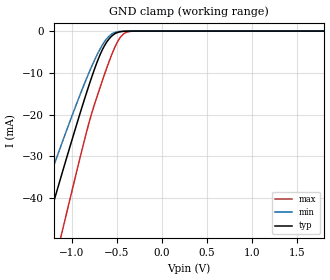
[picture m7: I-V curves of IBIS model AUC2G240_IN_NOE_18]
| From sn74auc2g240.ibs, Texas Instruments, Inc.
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[Model]   AUC2G240_IN_NOE_18
Model_type  Input
Vinl=0.5775
Vinh=1.2675
| variable   typ   min   max
C_comp   2.60pF   2.12pF   3.01pF
[Temperature Range]   40   100   -40
| Ambient temperature   25   85   -40
[Voltage range]   1.8   1.65   1.95
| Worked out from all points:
|   GND clamp passes 1 mA (typ) near -0.55 V on its own axis
[GND Clamp]
| AUC2G240_IN_NOE_18
|   Voltage   I(typ)   I(min)   I(max)
-3.6V     -223.1mA   -186.8mA   -268.3mA
-1.475V   -61.35mA   -49.06mA   -80.92mA
-1.43V    -57.96mA   -46.27mA   -76.89mA
-1.295V   -47.84mA   -37.96mA   -64.81mA
-1.145V   -36.73mA   -28.9mA    -51.37mA
-1.095V   -33.06mA   -25.94mA   -46.89mA
-830mV    -14.34mA   -11.03mA   -23.64mA
-685mV    -5.613mA   -4.259mA   -13.41mA
-560mV    -1.272mA   -762.6uA   -5.827mA
-485mV    -290.6uA   -142.1uA   -2.305mA
-420mV    -55.81uA   -27.03uA   -608.5uA
1.8V      213.9pA    308.4pA    246.3pA
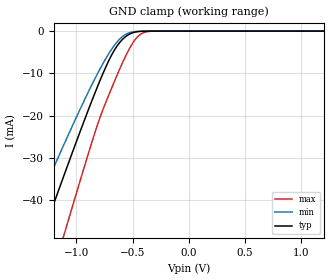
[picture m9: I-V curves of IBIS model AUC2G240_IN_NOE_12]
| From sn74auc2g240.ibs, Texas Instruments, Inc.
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[Model]   AUC2G240_IN_NOE_12
Model_type  Input
Vinl=0.385
Vinh=0.845
| variable   typ   min   max
C_comp   2.62pF   2.21pF   3.02pF
[Temperature Range]   40   100   -40
| Ambient temperature   25   85   -40
[Voltage range]   1.2   1.1   1.3
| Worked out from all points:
|   GND clamp passes 1 mA (typ) near -0.55 V on its own axis
[GND Clamp]
| AUC2G240_IN_NOE_12
|   Voltage   I(typ)   I(min)   I(max)
-3.6V     -223.1mA   -186.8mA   -268.3mA
-1.46V    -60.22mA   -48.13mA   -79.57mA
-1.415V   -56.83mA   -45.34mA   -75.55mA
-1.285V   -47.1mA    -37.35mA   -63.92mA
-1.12V    -34.89mA   -27.41mA   -49.13mA
-1.085V   -32.33mA   -25.35mA   -46mA
-830mV    -14.34mA   -11.03mA   -23.64mA
-690mV    -5.864mA   -4.456mA   -13.74mA
-570mV    -1.488mA   -922uA     -6.381mA
-440mV    -95.43uA   -45.59uA   -977.4uA
-320mV    -2.85uA    -1.757uA   -25.53uA
1.2V      140.4pA    230.7pA    130.8pA
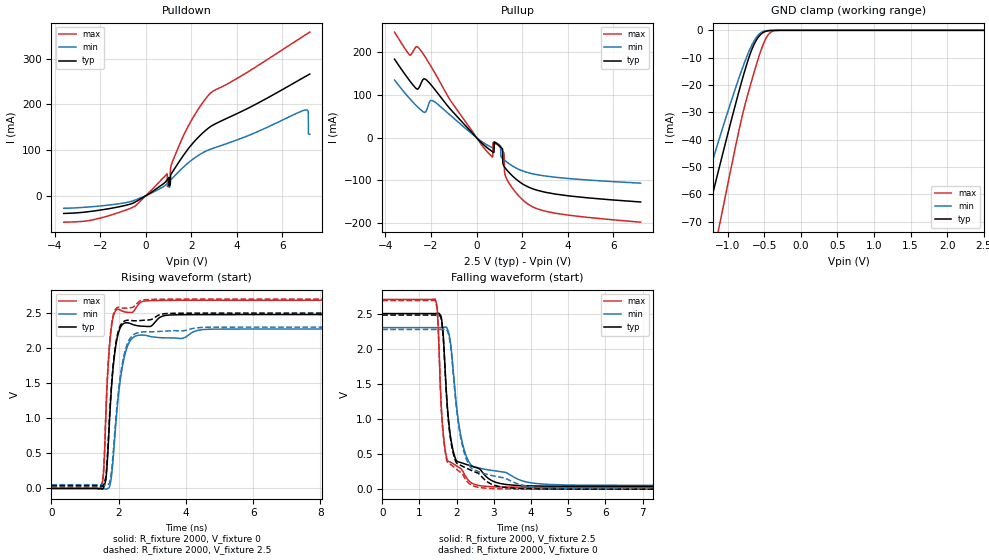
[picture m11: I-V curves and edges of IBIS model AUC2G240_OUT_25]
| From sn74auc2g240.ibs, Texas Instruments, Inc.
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[Model]   AUC2G240_OUT_25
Model_type  3-state
Enable   Active-Low
Vref =   0
Rref =   500
Cref =   30p
Vmeas =   1.25
| variable   typ   min   max
C_comp   4.93pF   4.38pF   5.28pF
| C_pullup   6.35pF   0.05pF   11.30pF
| C_pulldown   6.36pF   5.04pF   15.82pF
| C_tri-state   4.93pF   4.38pF   5.28pF
[Temperature Range]   40   100   -40
| Ambient temperature   25   85   -40
[Voltage range]   2.5   2.3   2.7
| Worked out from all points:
|   slope of the pulldown table from 0 to 0.375 V, typ, clamps not added: 30.9 ohm
|   slope of the pullup table from 0 to 0.375 V, typ, clamps not added: 19.2 ohm
|   GND clamp passes 1 mA (typ) near -0.53 V on its own axis
|   rising waveform, R_fixture 2000, V_fixture 0: 20-80 % time 223ps typ, 301ps min, 166ps max; typ from 0 V to 2.48 V
|   falling waveform, R_fixture 2000, V_fixture 2.5: 20-80 % time 253ps typ, 356ps min, 176ps max; typ from 2.5 V to 0.04 V
|   rising waveform, R_fixture 2000, V_fixture 2.5: 20-80 % time 222ps typ, 301ps min, 166ps max; typ from 0.04 V to 2.5 V
|   falling waveform, R_fixture 2000, V_fixture 0: 20-80 % time 256ps typ, 363ps min, 177ps max; typ from 2.48 V to 0 V
[GND Clamp]
| AUC2G240_OUT_25
|   Voltage   I(typ)   I(min)   I(max)
-3.6V     -324.8mA   -272.6mA   -395.3mA
-1.515V   -93.62mA   -75.35mA   -124.4mA
-1.455V   -87.03mA   -69.89mA   -116.5mA
-1.295V   -69.56mA   -55.5mA    -95.38mA
-1.105V   -49.1mA    -38.82mA   -70.28mA
-850mV    -22.72mA   -17.71mA   -37.11mA
-725mV    -11.19mA   -8.712mA   -23.46mA
-625mV    -4.389mA   -3.231mA   -14.1mA
-525mV    -974.6uA   -541.7uA   -5.852mA
-435mV    -119.5uA   -65.92uA   -1.256mA
-325mV    -4.911uA   -4.228uA   -43.96uA
2.5V      725.9pA    178.4nA    1.013nA
[Pulldown]
| AUC2G240_OUT_25
|   Voltage   I(typ)   I(min)   I(max)
-3.6V     -38.75mA   -27.46mA   -57.79mA
-580mV    -16.57mA   -11.5mA    -25.48mA
935mV     34.57mA    26.63mA    48.15mA
950mV     35.58mA    27.35mA    20.2mA
1.075V    24.55mA    33.22mA    46.33mA
1.62V     85.87mA    61.08mA    127.6mA
2.775V    148.9mA    100.6mA    221.1mA
7.005V    260.8mA    187.6mA    351.9mA
7.13V     264.4mA    184.5mA    355.9mA
7.135V    264.5mA    182.7mA    356mA
7.14V     264.6mA    135.1mA    356.2mA
7.2V      266.3mA    134.5mA    358.1mA
[Pullup]
| AUC2G240_OUT_25
|   Voltage   I(typ)   I(min)   I(max)
-3.6V     183.4mA    134.7mA    246.6mA
-2.935V   133mA      91.26mA    193mA
-2.48V    121.4mA    66.42mA    205.9mA
-1.895V   116.7mA    85.53mA    157.1mA
505mV     -25.26mA   -18.37mA   -35.17mA
1.03V     -20.52mA   -18.17mA   -22.58mA
1.14V     -26.75mA   -48.47mA   -30.66mA
1.2V      -66.47mA   -51.27mA   -36.41mA
1.23V     -69.04mA   -52.63mA   -81.1mA
1.32V     -74.92mA   -56.52mA   -96.36mA
2.17V     -112.6mA   -80.39mA   -151.9mA
7.2V      -150.3mA   -106.2mA   -197.4mA
[Ramp]
| AUC2G240_OUT_25
| variable   typ   min   max
dV/dt_r   1.49/2.24E-10   1.37/3.04E-10   1.62/1.68E-10
dV/dt_f   1.48/2.54E-10   1.35/3.59E-10   1.61/1.79E-10
R_load = 2000
[Rising Waveform]
| AUC2G240_OUT_25
R_fixture =   2000
C_fixture =   0
L_fixture =   0
V_fixture =   0
V_fixture_min = 0
V_fixture_max = 0
|   Time   V(typ)   V(min)   V(max)
0s        11.11nV    33.34nV    1.974nV
1.49ns    -6.69mV    -396.4uV   20.28mV
1.56ns    22.28mV    -3.606mV   299.4mV
1.625ns   142mV      -9.904mV   1.105V
1.715ns   845.8mV    9.895mV    1.946V
1.83ns    1.691V     384mV      2.43V
1.995ns   2.222V     1.335V     2.553V
2.17ns    2.356V     1.878V     2.518V
2.705ns   2.313V     2.187V     2.664V
20ns      2.479V     2.273V     2.683V
[Falling Waveform]
| AUC2G240_OUT_25
R_fixture =   2000
C_fixture =   0
L_fixture =   0
V_fixture =   2.5
V_fixture_min = 2.3
V_fixture_max = 2.7
|   Time   V(typ)   V(min)   V(max)
0s        2.5V       2.3V       2.7V
1.425ns   2.5V       2.3V       2.706V
1.49ns    2.502V     2.3V       2.473V
1.6ns     2.404V     2.301V     1.065V
1.73ns    1.343V     2.302V     446.9mV
1.975ns   426.6mV    1.3V       338.9mV
2.205ns   362.2mV    556.6mV    216mV
2.53ns    306.1mV    311.6mV    60.61mV
3.89ns    47.89mV    101.3mV    27.31mV
20ns      40.45mV    53.08mV    26.22mV
[Rising Waveform]
| AUC2G240_OUT_25
R_fixture =   2000
C_fixture =   0
L_fixture =   0
V_fixture =   2.5
V_fixture_min = 2.3
V_fixture_max = 2.7
|   Time   V(typ)   V(min)   V(max)
0s        40.42mV    53.07mV    26.21mV
1.49ns    34.02mV    52.67mV    46.93mV
1.555ns   58.74mV    50.03mV    290.1mV
1.625ns   189.5mV    43.92mV    1.137V
1.72ns    945.4mV    70.54mV    2.004V
1.83ns    1.726V     459mV      2.454V
1.995ns   2.251V     1.388V     2.583V
2.165ns   2.385V     1.91V      2.57V
2.69ns    2.396V     2.23V      2.683V
20ns      2.5V       2.3V       2.7V
[Falling Waveform]
| AUC2G240_OUT_25
R_fixture =   2000
C_fixture =   0
L_fixture =   0
V_fixture =   0
V_fixture_min = 0
V_fixture_max = 0
|   Time   V(typ)   V(min)   V(max)
0s        2.479V     2.273V     2.683V
1.425ns   2.478V     2.273V     2.689V
1.49ns    2.479V     2.273V     2.453V
1.6ns     2.379V     2.274V     1.047V
1.73ns    1.314V     2.272V     423.5mV
1.965ns   408.2mV    1.315V     297.8mV
2.19ns    317.9mV    546.5mV    187.1mV
2.505ns   242.4mV    267.8mV    34.86mV
4.72ns    1.41mV     8.657mV    268.1uV
20ns      27.49uV    4.446uV    11.76uV
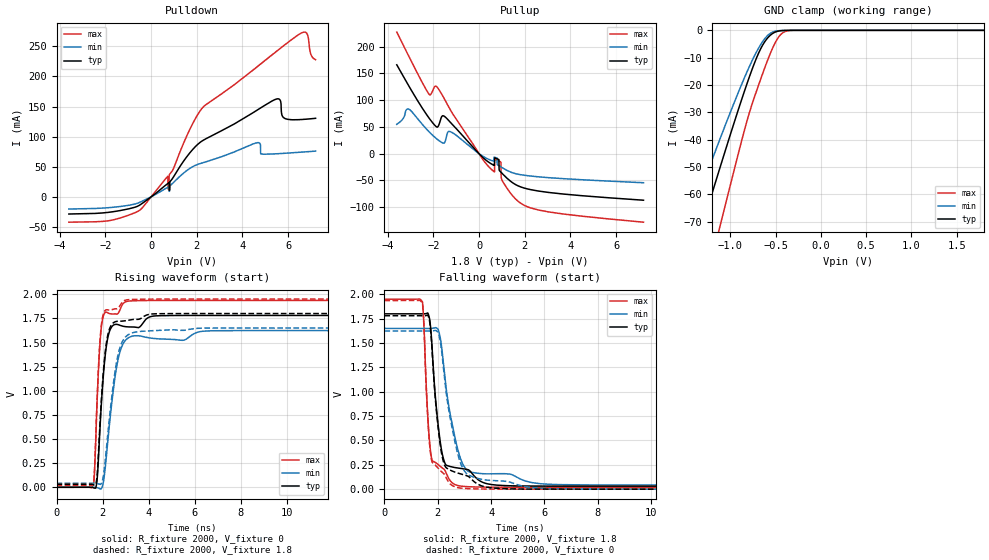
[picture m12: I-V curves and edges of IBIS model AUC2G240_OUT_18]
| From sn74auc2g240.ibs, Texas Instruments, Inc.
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[Model]   AUC2G240_OUT_18
Model_type  3-state
Enable   Active-Low
Vref =   0
Rref =   1000
Cref =   30p
Vmeas =   0.9
| variable   typ   min   max
C_comp   5.15pF   4.59pF   5.41pF
| C_pullup   5.89pF   1.37pF   12.98pF
| C_pulldown   6.42pF   5.22pF   15.40pF
| C_tri-state   5.15pF   4.59pF   5.41pF
[Temperature Range]   40   100   -40
| Ambient temperature   25   85   -40
[Voltage range]   1.8   1.65   1.95
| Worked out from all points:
|   slope of the pulldown table from 0 to 0.27 V, typ, clamps not added: 34.3 ohm
|   slope of the pullup table from 0 to 0.27 V, typ, clamps not added: 24.6 ohm
|   GND clamp passes 1 mA (typ) near -0.53 V on its own axis
|   rising waveform, R_fixture 2000, V_fixture 0: 20-80 % time 311ps typ, 483ps min, 215ps max; typ from 0 V to 1.78 V
|   falling waveform, R_fixture 2000, V_fixture 1.8: 20-80 % time 363ps typ, 597ps min, 222ps max; typ from 1.8 V to 0.031 V
|   rising waveform, R_fixture 2000, V_fixture 1.8: 20-80 % time 309ps typ, 481ps min, 214ps max; typ from 0.031 V to 1.8 V
|   falling waveform, R_fixture 2000, V_fixture 0: 20-80 % time 364ps typ, 594ps min, 222ps max; typ from 1.78 V to 0 V
[GND Clamp]
| AUC2G240_OUT_18
|   Voltage   I(typ)   I(min)   I(max)
-3.6V     -324.8mA   -272.6mA   -395.3mA
-1.48V    -89.78mA   -72.17mA   -119.8mA
-1.435V   -84.84mA   -68.08mA   -113.9mA
-1.3V     -70.1mA    -55.95mA   -96.04mA
-1.105V   -49.1mA    -38.82mA   -70.28mA
-830mV    -20.77mA   -16.17mA   -34.67mA
-685mV    -8.07mA    -6.262mA   -19.65mA
-565mV    -1.967mA   -1.239mA   -8.908mA
-490mV    -465.2uA   -242.6uA   -3.617mA
-425mV    -91.43uA   -52.01uA   -990.1uA
-300mV    -2.28uA    -2.125uA   -16.99uA
1.8V      471.4pA    37.83nA    507.7pA
[Pulldown]
| AUC2G240_OUT_18
|   Voltage   I(typ)   I(min)   I(max)
-3.6V     -28.49mA   -20.22mA   -42.08mA
-710mV    -17.24mA   -11.96mA   -26.36mA
730mV     22.14mA    15.83mA    34.29mA
780mV     23.67mA    17.08mA    13.96mA
805mV     10.91mA    9.302mA    37.17mA
2.23V     92.83mA    56.26mA    147.2mA
4.65V     144.3mA    90.06mA    216.4mA
5.505V    162.8mA    71.64mA    242.3mA
5.79V     131.9mA    72.29mA    250.8mA
6.445V    128.2mA    73.96mA    269.3mA
6.815V    129.2mA    74.96mA    271.7mA
7.2V      130.5mA    76.01mA    228mA
[Pullup]
| AUC2G240_OUT_18
|   Voltage   I(typ)   I(min)   I(max)
-3.6V     166.1mA    54.83mA    227.3mA
-3.08V    127.2mA    83.38mA    182.7mA
-2.18V    66.16mA    40.7mA     110.8mA
-1.91V    51.96mA    29.83mA    126.4mA
-1.51V    69.63mA    20.5mA     101.9mA
-1.25V    58.38mA    41.07mA    81.58mA
385mV     -14.76mA   -9.808mA   -22.53mA
870mV     -11.11mA   -22.27mA   -13.48mA
955mV     -34.36mA   -24.54mA   -15.75mA
1.015V    -36.99mA   -26.15mA   -50.39mA
1.755V    -60.96mA   -38.77mA   -90.45mA
7.2V      -86.99mA   -54.32mA   -128.1mA
[Ramp]
| AUC2G240_OUT_18
| variable   typ   min   max
dV/dt_r   1.07/3.12E-10   0.99/4.88E-10   1.16/2.18E-10
dV/dt_f   1.07/3.66E-10   0.97/6.03E-10   1.16/2.23E-10
R_load = 2000
[Rising Waveform]
| AUC2G240_OUT_18
R_fixture =   2000
C_fixture =   0
L_fixture =   0
V_fixture =   0
V_fixture_min = 0
V_fixture_max = 0
|   Time   V(typ)   V(min)   V(max)
0s        8.423nV    29.16nV    1.166nV
1.615ns   -6.247mV   655.4uV    45.79mV
1.765ns   88.11mV    -3.768mV   908.5mV
1.875ns   559.3mV    -14.29mV   1.452V
1.98ns    987.6mV    1.474mV    1.717V
2.135ns   1.41V      252mV      1.814V
2.31ns    1.623V     679.9mV    1.799V
2.645ns   1.687V     1.294V     1.796V
3.005ns   1.664V     1.527V     1.923V
20ns      1.78V      1.624V     1.936V
[Falling Waveform]
| AUC2G240_OUT_18
R_fixture =   2000
C_fixture =   0
L_fixture =   0
V_fixture =   1.8
V_fixture_min = 1.65
V_fixture_max = 1.95
|   Time   V(typ)   V(min)   V(max)
0s        1.8V       1.65V      1.95V
1.425ns   1.8V       1.65V      1.923V
1.63ns    1.806V     1.649V     728.3mV
1.765ns   1.548V     1.651V     322.8mV
1.935ns   872mV      1.657V     269.6mV
2.155ns   380.3mV    1.438V     221mV
2.69ns    219.9mV    476mV      42.31mV
3.155ns   198.6mV    181.5mV    25.24mV
5.835ns   31.64mV    56.33mV    19.59mV
20ns      30.97mV    42.25mV    19.49mV
[Rising Waveform]
| AUC2G240_OUT_18
R_fixture =   2000
C_fixture =   0
L_fixture =   0
V_fixture =   1.8
V_fixture_min = 1.65
V_fixture_max = 1.95
|   Time   V(typ)   V(min)   V(max)
0s        30.94mV    42.24mV    19.47mV
1.58ns    27.94mV    42.78mV    40.49mV
1.645ns   24.05mV    42.57mV    165.3mV
1.755ns   105.3mV    39.4mV     873.8mV
1.87ns    584.7mV    32.27mV    1.459V
1.985ns   1.043V     62.79mV    1.746V
2.29ns    1.635V     702.4mV    1.837V
2.615ns   1.719V     1.309V     1.849V
2.95ns    1.724V     1.544V     1.935V
20ns      1.8V       1.65V      1.95V
[Falling Waveform]
| AUC2G240_OUT_18
R_fixture =   2000
C_fixture =   0
L_fixture =   0
V_fixture =   0
V_fixture_min = 0
V_fixture_max = 0
|   Time   V(typ)   V(min)   V(max)
0s        1.78V      1.624V     1.936V
1.425ns   1.78V      1.623V     1.908V
1.63ns    1.785V     1.623V     711.2mV
1.76ns    1.539V     1.624V     311mV
1.93ns    862.5mV    1.629V     240.1mV
2.14ns    372mV      1.43V      180.2mV
2.635ns   176mV      497.1mV    24.74mV
3.13ns    133.4mV    149.3mV    5.66mV
5.545ns   906.7uV    16.16mV    128.9uV
20ns      31.93uV    9.085uV    13.35uV
